VERSION 5.7 ;
  NOWIREEXTENSIONATPIN ON ;
  DIVIDERCHAR "/" ;
  BUSBITCHARS "[]" ;
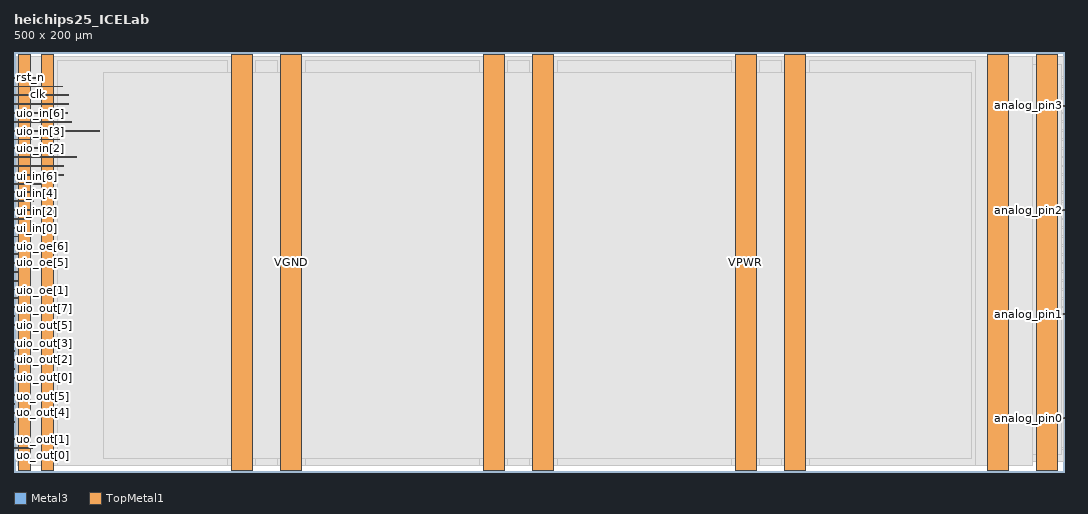
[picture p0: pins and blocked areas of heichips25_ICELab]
MACRO heichips25_ICELab
  CLASS BLOCK ;
  FOREIGN heichips25_ICELab ;
  ORIGIN 0.000 0.000 ;
  SIZE 500.000 BY 200.000 ;
  PIN analog_pin0
    DIRECTION INOUT ;
    USE SIGNAL ;
    ANTENNADIFFAREA 3.578400 ;
    PORT
      LAYER Metal3 ;
        RECT 498.650 25.420 500.000 25.820 ;
    END
  END analog_pin0
  PIN analog_pin1
    DIRECTION INOUT ;
    USE SIGNAL ;
    ANTENNADIFFAREA 0.298200 ;
    PORT
      LAYER Metal3 ;
        RECT 499.600 74.980 500.000 75.380 ;
    END
  END analog_pin1
  PIN analog_pin2
    DIRECTION INOUT ;
    USE SIGNAL ;
    ANTENNAGATEAREA 1.500000 ;
    PORT
      LAYER Metal3 ;
        RECT 491.340 124.540 500.000 124.940 ;
    END
  END analog_pin2
  PIN analog_pin3
    DIRECTION INOUT ;
    USE SIGNAL ;
    ANTENNAGATEAREA 2.190000 ;
    PORT
      LAYER Metal3 ;
        RECT 494.550 174.100 500.000 174.500 ;
    END
  END analog_pin3
  PIN clk
    DIRECTION INPUT ;
    USE SIGNAL ;
    ANTENNAGATEAREA 0.725400 ;
    PORT
      LAYER Metal3 ;
        RECT 0.000 183.340 23.140 183.740 ;
    END
  END clk
  PIN ena
    DIRECTION INPUT ;
    USE SIGNAL ;
    ANTENNAGATEAREA 23.614399 ;
    PORT
      LAYER Metal3 ;
        RECT 0.000 179.140 26.080 179.540 ;
    END
  END ena
  PIN rst_n
    DIRECTION INPUT ;
    USE SIGNAL ;
    ANTENNAGATEAREA 0.725400 ;
    PORT
      LAYER Metal3 ;
        RECT 0.000 187.540 12.100 187.940 ;
    END
  END rst_n
  PIN ui_in[0]
    DIRECTION INPUT ;
    USE SIGNAL ;
    ANTENNAGATEAREA 1.310400 ;
    PORT
      LAYER Metal3 ;
        RECT 0.000 111.940 2.135 112.340 ;
    END
  END ui_in[0]
  PIN ui_in[1]
    DIRECTION INPUT ;
    USE SIGNAL ;
    ANTENNAGATEAREA 1.310400 ;
    PORT
      LAYER Metal3 ;
        RECT 0.000 116.140 3.905 116.540 ;
    END
  END ui_in[1]
  PIN ui_in[2]
    DIRECTION INPUT ;
    USE SIGNAL ;
    ANTENNAGATEAREA 5.241600 ;
    PORT
      LAYER Metal3 ;
        RECT 0.000 120.340 5.755 120.740 ;
    END
  END ui_in[2]
  PIN ui_in[3]
    DIRECTION INPUT ;
    USE SIGNAL ;
    ANTENNAGATEAREA 5.241600 ;
    PORT
      LAYER Metal3 ;
        RECT 0.000 124.540 7.635 124.940 ;
    END
  END ui_in[3]
  PIN ui_in[4]
    DIRECTION INPUT ;
    USE SIGNAL ;
    ANTENNAGATEAREA 20.966400 ;
    PORT
      LAYER Metal3 ;
        RECT 0.000 128.740 9.515 129.140 ;
    END
  END ui_in[4]
  PIN ui_in[5]
    DIRECTION INPUT ;
    USE SIGNAL ;
    ANTENNAGATEAREA 20.966400 ;
    PORT
      LAYER Metal3 ;
        RECT 0.000 132.940 11.435 133.340 ;
    END
  END ui_in[5]
  PIN ui_in[6]
    DIRECTION INPUT ;
    USE SIGNAL ;
    ANTENNAGATEAREA 0.445200 ;
    PORT
      LAYER Metal3 ;
        RECT 0.000 137.140 13.165 137.540 ;
    END
  END ui_in[6]
  PIN ui_in[7]
    DIRECTION INPUT ;
    USE SIGNAL ;
    ANTENNAGATEAREA 0.445200 ;
    PORT
      LAYER Metal3 ;
        RECT 0.000 141.340 23.570 141.740 ;
    END
  END ui_in[7]
  PIN uio_in[0]
    DIRECTION INPUT ;
    USE SIGNAL ;
    ANTENNAGATEAREA 2.620800 ;
    PORT
      LAYER Metal3 ;
        RECT 0.000 145.540 23.590 145.940 ;
    END
  END uio_in[0]
  PIN uio_in[1]
    DIRECTION INPUT ;
    USE SIGNAL ;
    ANTENNAGATEAREA 2.620800 ;
    PORT
      LAYER Metal3 ;
        RECT 0.000 149.740 29.870 150.140 ;
    END
  END uio_in[1]
  PIN uio_in[2]
    DIRECTION INPUT ;
    USE SIGNAL ;
    ANTENNAGATEAREA 18.580000 ;
    PORT
      LAYER Metal3 ;
        RECT 0.000 153.940 15.135 154.340 ;
    END
  END uio_in[2]
  PIN uio_in[3]
    DIRECTION INPUT ;
    USE SIGNAL ;
    ANTENNAGATEAREA 0.327600 ;
    PORT
      LAYER Metal3 ;
        RECT 0.000 158.140 21.530 158.540 ;
    END
  END uio_in[3]
  PIN uio_in[4]
    DIRECTION INPUT ;
    USE SIGNAL ;
    ANTENNAGATEAREA 2.901600 ;
    PORT
      LAYER Metal3 ;
        RECT 0.000 162.340 40.920 162.740 ;
    END
  END uio_in[4]
  PIN uio_in[5]
    DIRECTION INPUT ;
    USE SIGNAL ;
    ANTENNAGATEAREA 0.967200 ;
    PORT
      LAYER Metal3 ;
        RECT 0.000 166.540 27.370 166.940 ;
    END
  END uio_in[5]
  PIN uio_in[6]
    DIRECTION INPUT ;
    USE SIGNAL ;
    ANTENNAGATEAREA 1.835600 ;
    PORT
      LAYER Metal3 ;
        RECT 0.000 170.740 25.700 171.140 ;
    END
  END uio_in[6]
  PIN uio_in[7]
    DIRECTION INPUT ;
    USE SIGNAL ;
    ANTENNAGATEAREA 3.385200 ;
    PORT
      LAYER Metal3 ;
        RECT 0.000 174.940 25.900 175.340 ;
    END
  END uio_in[7]
  PIN uio_oe[0]
    DIRECTION OUTPUT ;
    USE SIGNAL ;
    ANTENNAGATEAREA 4.800000 ;
    ANTENNADIFFAREA 5084.195312 ;
    PORT
      LAYER Metal3 ;
        RECT 0.000 78.340 1.760 78.740 ;
    END
  END uio_oe[0]
  PIN uio_oe[1]
    DIRECTION OUTPUT ;
    USE SIGNAL ;
    ANTENNAGATEAREA 4.800000 ;
    ANTENNADIFFAREA 5084.195312 ;
    PORT
      LAYER Metal3 ;
        RECT 0.000 82.540 1.760 82.940 ;
    END
  END uio_oe[1]
  PIN uio_oe[2]
    DIRECTION OUTPUT ;
    USE SIGNAL ;
    PORT
      LAYER Metal3 ;
        RECT 0.000 86.740 1.760 87.140 ;
    END
  END uio_oe[2]
  PIN uio_oe[3]
    DIRECTION OUTPUT ;
    USE SIGNAL ;
    PORT
      LAYER Metal3 ;
        RECT 0.000 90.940 1.760 91.340 ;
    END
  END uio_oe[3]
  PIN uio_oe[4]
    DIRECTION OUTPUT ;
    USE SIGNAL ;
    PORT
      LAYER Metal3 ;
        RECT 0.000 95.140 1.760 95.540 ;
    END
  END uio_oe[4]
  PIN uio_oe[5]
    DIRECTION OUTPUT ;
    USE SIGNAL ;
    PORT
      LAYER Metal3 ;
        RECT 0.000 99.340 1.760 99.740 ;
    END
  END uio_oe[5]
  PIN uio_oe[6]
    DIRECTION OUTPUT ;
    USE SIGNAL ;
    PORT
      LAYER Metal3 ;
        RECT 0.000 103.540 1.760 103.940 ;
    END
  END uio_oe[6]
  PIN uio_oe[7]
    DIRECTION OUTPUT ;
    USE SIGNAL ;
    PORT
      LAYER Metal3 ;
        RECT 0.000 107.740 1.760 108.140 ;
    END
  END uio_oe[7]
  PIN uio_out[0]
    DIRECTION OUTPUT ;
    USE SIGNAL ;
    PORT
      LAYER Metal3 ;
        RECT 0.000 44.740 0.400 45.140 ;
    END
  END uio_out[0]
  PIN uio_out[1]
    DIRECTION OUTPUT ;
    USE SIGNAL ;
    PORT
      LAYER Metal3 ;
        RECT 0.000 48.940 0.400 49.340 ;
    END
  END uio_out[1]
  PIN uio_out[2]
    DIRECTION OUTPUT ;
    USE SIGNAL ;
    PORT
      LAYER Metal3 ;
        RECT 0.000 53.140 0.400 53.540 ;
    END
  END uio_out[2]
  PIN uio_out[3]
    DIRECTION OUTPUT ;
    USE SIGNAL ;
    PORT
      LAYER Metal3 ;
        RECT 0.000 57.340 0.400 57.740 ;
    END
  END uio_out[3]
  PIN uio_out[4]
    DIRECTION OUTPUT ;
    USE SIGNAL ;
    PORT
      LAYER Metal3 ;
        RECT 0.000 61.540 0.400 61.940 ;
    END
  END uio_out[4]
  PIN uio_out[5]
    DIRECTION OUTPUT ;
    USE SIGNAL ;
    PORT
      LAYER Metal3 ;
        RECT 0.000 65.740 0.400 66.140 ;
    END
  END uio_out[5]
  PIN uio_out[6]
    DIRECTION OUTPUT ;
    USE SIGNAL ;
    PORT
      LAYER Metal3 ;
        RECT 0.000 69.940 0.400 70.340 ;
    END
  END uio_out[6]
  PIN uio_out[7]
    DIRECTION OUTPUT ;
    USE SIGNAL ;
    PORT
      LAYER Metal3 ;
        RECT 0.000 74.140 0.400 74.540 ;
    END
  END uio_out[7]
  PIN uo_out[0]
    DIRECTION OUTPUT ;
    USE SIGNAL ;
    ANTENNADIFFAREA 1.413600 ;
    PORT
      LAYER Metal3 ;
        RECT 0.000 11.140 8.700 11.540 ;
    END
  END uo_out[0]
  PIN uo_out[1]
    DIRECTION OUTPUT ;
    USE SIGNAL ;
    PORT
      LAYER Metal3 ;
        RECT 0.000 15.340 0.400 15.740 ;
    END
  END uo_out[1]
  PIN uo_out[2]
    DIRECTION OUTPUT ;
    USE SIGNAL ;
    PORT
      LAYER Metal3 ;
        RECT 0.000 19.540 0.400 19.940 ;
    END
  END uo_out[2]
  PIN uo_out[3]
    DIRECTION OUTPUT ;
    USE SIGNAL ;
    PORT
      LAYER Metal3 ;
        RECT 0.000 23.740 0.400 24.140 ;
    END
  END uo_out[3]
  PIN uo_out[4]
    DIRECTION OUTPUT ;
    USE SIGNAL ;
    PORT
      LAYER Metal3 ;
        RECT 0.000 27.940 0.400 28.340 ;
    END
  END uo_out[4]
  PIN uo_out[5]
    DIRECTION OUTPUT ;
    USE SIGNAL ;
    PORT
      LAYER Metal3 ;
        RECT 0.000 32.140 0.400 32.540 ;
    END
  END uo_out[5]
  PIN uo_out[6]
    DIRECTION OUTPUT ;
    USE SIGNAL ;
    PORT
      LAYER Metal3 ;
        RECT 0.000 36.340 0.400 36.740 ;
    END
  END uo_out[6]
  PIN uo_out[7]
    DIRECTION OUTPUT ;
    USE SIGNAL ;
    PORT
      LAYER Metal3 ;
        RECT 0.000 40.540 0.400 40.940 ;
    END
  END uo_out[7]
  PIN VPWR
    DIRECTION INOUT ;
    USE POWER ;
    PORT
      LAYER TopMetal1 ;
        RECT 343.350 0.770 353.350 198.770 ;
    END
    PORT
      LAYER TopMetal1 ;
        RECT 223.350 0.770 233.350 198.770 ;
    END
    PORT
      LAYER TopMetal1 ;
        RECT 103.350 0.770 113.350 198.770 ;
    END
    PORT
      LAYER TopMetal1 ;
        RECT 1.960 0.770 7.960 198.770 ;
    END
    PORT
      LAYER TopMetal1 ;
        RECT 463.350 0.770 473.350 198.770 ;
    END
  END VPWR
  PIN VGND
    DIRECTION INOUT ;
    USE GROUND ;
    PORT
      LAYER TopMetal1 ;
        RECT 366.960 0.770 376.960 198.770 ;
    END
    PORT
      LAYER TopMetal1 ;
        RECT 126.960 0.770 136.960 198.770 ;
    END
    PORT
      LAYER TopMetal1 ;
        RECT 246.960 0.770 256.960 198.770 ;
    END
    PORT
      LAYER TopMetal1 ;
        RECT 12.960 0.770 18.960 198.770 ;
    END
    PORT
      LAYER TopMetal1 ;
        RECT 486.960 0.770 496.960 198.770 ;
    END
  END VGND
  OBS
      LAYER GatPoly ;
        RECT 10.590 10.160 477.830 194.780 ;
      LAYER Metal1 ;
        RECT 10.590 10.250 477.810 194.310 ;
      LAYER Metal2 ;
        RECT 2.110 8.300 477.810 194.600 ;
      LAYER Metal3 ;
        RECT 1.360 188.150 499.600 197.770 ;
        RECT 12.310 187.330 499.600 188.150 ;
        RECT 1.360 183.950 499.600 187.330 ;
        RECT 23.350 183.130 499.600 183.950 ;
        RECT 1.360 179.750 499.600 183.130 ;
        RECT 26.290 178.930 499.600 179.750 ;
        RECT 1.360 175.550 499.600 178.930 ;
        RECT 26.110 174.730 499.600 175.550 ;
        RECT 1.360 174.710 499.600 174.730 ;
        RECT 1.360 173.890 494.340 174.710 ;
        RECT 1.360 171.350 499.600 173.890 ;
        RECT 25.910 170.530 499.600 171.350 ;
        RECT 1.360 167.150 499.600 170.530 ;
        RECT 27.580 166.330 499.600 167.150 ;
        RECT 1.360 162.950 499.600 166.330 ;
        RECT 41.130 162.130 499.600 162.950 ;
        RECT 1.360 158.750 499.600 162.130 ;
        RECT 21.740 157.930 499.600 158.750 ;
        RECT 1.360 154.550 499.600 157.930 ;
        RECT 15.345 153.730 499.600 154.550 ;
        RECT 1.360 150.350 499.600 153.730 ;
        RECT 30.080 149.530 499.600 150.350 ;
        RECT 1.360 146.150 499.600 149.530 ;
        RECT 23.800 145.330 499.600 146.150 ;
        RECT 1.360 141.950 499.600 145.330 ;
        RECT 23.780 141.130 499.600 141.950 ;
        RECT 1.360 137.750 499.600 141.130 ;
        RECT 13.375 136.930 499.600 137.750 ;
        RECT 1.360 133.550 499.600 136.930 ;
        RECT 11.645 132.730 499.600 133.550 ;
        RECT 1.360 129.350 499.600 132.730 ;
        RECT 9.725 128.530 499.600 129.350 ;
        RECT 1.360 125.150 499.600 128.530 ;
        RECT 7.845 124.330 491.130 125.150 ;
        RECT 1.360 120.950 499.600 124.330 ;
        RECT 5.965 120.130 499.600 120.950 ;
        RECT 1.360 116.750 499.600 120.130 ;
        RECT 4.115 115.930 499.600 116.750 ;
        RECT 1.360 112.550 499.600 115.930 ;
        RECT 2.345 111.730 499.600 112.550 ;
        RECT 1.360 108.350 499.600 111.730 ;
        RECT 1.970 107.530 499.600 108.350 ;
        RECT 1.360 104.150 499.600 107.530 ;
        RECT 1.970 103.330 499.600 104.150 ;
        RECT 1.360 99.950 499.600 103.330 ;
        RECT 1.970 99.130 499.600 99.950 ;
        RECT 1.360 95.750 499.600 99.130 ;
        RECT 1.970 94.930 499.600 95.750 ;
        RECT 1.360 91.550 499.600 94.930 ;
        RECT 1.970 90.730 499.600 91.550 ;
        RECT 1.360 87.350 499.600 90.730 ;
        RECT 1.970 86.530 499.600 87.350 ;
        RECT 1.360 83.150 499.600 86.530 ;
        RECT 1.970 82.330 499.600 83.150 ;
        RECT 1.360 78.950 499.600 82.330 ;
        RECT 1.970 78.130 499.600 78.950 ;
        RECT 1.360 75.590 499.600 78.130 ;
        RECT 1.360 74.770 499.390 75.590 ;
        RECT 1.360 26.030 499.600 74.770 ;
        RECT 1.360 25.210 498.440 26.030 ;
        RECT 1.360 11.750 499.600 25.210 ;
        RECT 8.910 10.930 499.600 11.750 ;
        RECT 1.360 4.805 499.600 10.930 ;
      LAYER Metal4 ;
        RECT 3.150 8.300 498.870 193.990 ;
      LAYER Metal5 ;
        RECT 1.710 3.180 484.970 197.840 ;
      LAYER TopMetal1 ;
        RECT 20.600 3.180 101.710 195.810 ;
        RECT 114.990 3.180 125.320 195.810 ;
        RECT 138.600 3.180 221.710 195.810 ;
        RECT 234.990 3.180 245.320 195.810 ;
        RECT 258.600 3.180 341.710 195.810 ;
        RECT 354.990 3.180 365.320 195.810 ;
        RECT 378.600 3.180 457.640 195.810 ;
      LAYER TopMetal2 ;
        RECT 42.450 6.650 455.800 190.160 ;
  END
END heichips25_ICELab
END LIBRARY

